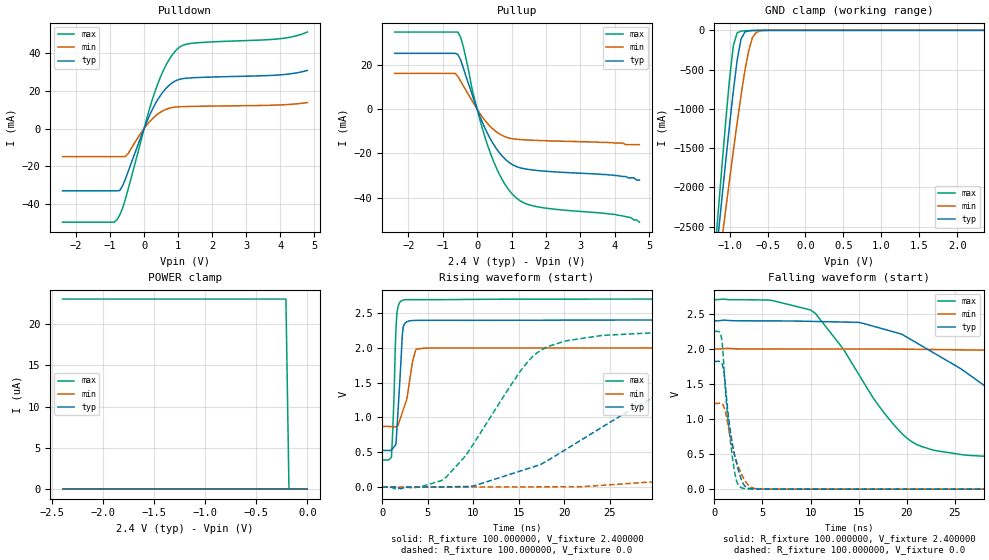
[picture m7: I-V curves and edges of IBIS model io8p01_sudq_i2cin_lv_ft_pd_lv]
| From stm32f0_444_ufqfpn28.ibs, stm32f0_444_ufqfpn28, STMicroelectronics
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|   Model io8p01_sudq_i2cin_lv_ft_pd_lv
[Model]  io8p01_sudq_i2cin_lv_ft_pd_lv
Model_type I/O
Polarity   Non-Inverting
Enable   Active-Low
Vinl =   0.720000V
Vinh =   1.680000V
Vmeas =  1.200000V
Cref =   50.000000pF
Rref =   100.000000M
Vref =   0.0V
C_comp   2.067900pF   1.988600pF   2.164800pF
[Temperature Range]   25.000000   0.125000k   -40.000000
[Pullup Reference]   2.400000V   2.000000V   2.700000V
[Pulldown Reference]   0.0V   0.0V   0.0V
[POWER Clamp Reference]   2.400000V   2.000000V   2.700000V
[GND Clamp Reference]   0.0V   0.0V   0.0V
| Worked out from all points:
|   slope of the pulldown table from 0 to 0.36 V, typ, clamps not added: 25.5 ohm
|   slope of the pullup table from 0 to 0.36 V, typ, clamps not added: 28.4 ohm
|   GND clamp passes 1 mA (typ) near -0.64 V on its own axis
|   rising waveform, R_fixture 100.000000, V_fixture 2.400000: 20-80 % time 500ps typ, 1.02ns min, 335ps max; typ from 0.525 V to 2.4 V
|   rising waveform, R_fixture 100.000000, V_fixture 0.0: 20-80 % time 14.6ns typ, 43.1ns min, 6.86ns max; typ from 0 V to 1.82 V
|   falling waveform, R_fixture 100.000000, V_fixture 2.400000: 20-80 % time 12.9ns typ, 31.1ns min, 7.07ns max; typ from 2.4 V to 0.525 V
|   falling waveform, R_fixture 100.000000, V_fixture 0.0: 20-80 % time 1.16ns typ, 1.39ns min, 919ps max; typ from 1.82 V to 0 V
[Pulldown]
|Voltage   I(typ)   I(min)   I(max)
-2.4V     -33.16mA   -14.98mA   -49.86mA
-880mV    -33.16mA   -14.98mA   -49.86mA
-800mV    -33.16mA   -14.98mA   -48.55mA
-640mV    -30.75mA   -14.98mA   -42.77mA
-480mV    -23.43mA   -13.57mA   -32.92mA
80mV      3.651mA    1.905mA    5.506mA
400mV     15.37mA    7.665mA    23.73mA
720mV     22.75mA    10.69mA    36.23mA
1.04V     26.18mA    11.57mA    43.27mA
1.52V     27.09mA    11.81mA    45.55mA
4V        28.55mA    12.55mA    47.81mA
4.8V      30.9mA     13.81mA    51.31mA
[Pullup]
|Voltage   I(typ)   I(min)   I(max)
-2.4V     25.18mA    16.13mA    34.78mA
-640mV    25.18mA    16.13mA    34.78mA
-560mV    24.71mA    14.76mA    34.78mA
-400mV    18.52mA    10.49mA    28.1mA
-160mV    7.343mA    4.152mA    10.02mA
80mV      -3.229mA   -1.94mA    -4.736mA
400mV     -13.82mA   -8.08mA    -20.45mA
800mV     -22.31mA   -12.38mA   -33.66mA
1.2V      -26.24mA   -13.65mA   -40.82mA
1.76V     -27.69mA   -14.12mA   -44.06mA
4V        -29.9mA    -15.3mA    -47.5mA
4.72V     -32mA      -16mA      -51mA
[GND_clamp]
|Voltage   I(typ)   I(min)   I(max)
-2.4V     -9.567A    -9.921A    -9.731A
-1.2V     -3.09A     -3.428A    -2.911A
-1.15V    -2.606A    -3.04A     -2.31A
-1.1V     -2.127A    -2.655A    -1.719A
-1.05V    -1.657A    -2.274A    -1.146A
-950mV    -765.3mA   -1.53A     -190.2mA
-900mV    -376.6mA   -1.172A    -30.82mA
-850mV    -112.3mA   -832.5mA   -10.25mA
-750mV    -6.584mA   -264.6mA   -4.043mA
-700mV    -2.596mA   -94.27mA   -2.346mA
-600mV    -430uA     -8.168mA   -383.4uA
2.35V     59.64uA    46.24uA    66.77uA
[POWER_clamp]
|Voltage   I(typ)   I(min)   I(max)
-2.4V     0A         0A         23.03uA
-210mV    0A         0A         23.03uA
-180mV    0A         0A         0A
0V        0A         0A         0A
[Ramp]
| variable   typ   min   max
dV/dt_r  1.09212/14.56809n   0.73266/43.05273n   1.34886/6.82630n
dV/dt_f  1.12434/12.85256n   0.67775/31.09011n   1.38699/7.06475n
R_load = 100.000000
[Rising Waveform]
R_fixture= 100.000000
V_fixture= 2.400000
V_fixture_min= 2.000000
V_fixture_max= 2.700000
|time   V(typ)   V(min)   V(max)
0s        524.8mV    868.7mV    387.2mV
1.001ns   532.9mV    867mV      427.3mV
1.301ns   579.1mV    865.4mV    1.37V
1.401ns   594.6mV    865.1mV    1.926V
1.502ns   617.3mV    864.8mV    2.291V
1.702ns   1.048V     875.3mV    2.575V
2.202ns   2.193V     1.071V     2.68V
2.603ns   2.365V     1.228V     2.689V
3.704ns   2.393V     1.98V      2.691V
49.85ns   2.399V     1.999V     2.699V
[Rising Waveform]
R_fixture= 100.000000
V_fixture= 0.0
V_fixture_min= 0.0
V_fixture_max= 0.0
|time   V(typ)   V(min)   V(max)
0s        1.433nV    15.35nV    1.088nV
6.507ns   646.2uV    89.27uV    90.97mV
9.51ns    7.691mV    -441.4uV   514.6mV
16.52ns   284.6mV    1.37mV     1.871V
24.52ns   887.2mV    26.48mV    2.179V
36.54ns   1.614V     133.7mV    2.237V
56.06ns   1.793V     469.1mV    2.248V
89.09ns   1.819V     1.005V     2.248V
109.1ns   1.82V      1.141V     2.248V
249.2ns   1.82V      1.221V     2.248V
[Falling Waveform]
R_fixture= 100.000000
V_fixture= 2.400000
V_fixture_min= 2.000000
V_fixture_max= 2.700000
|time   V(typ)   V(min)   V(max)
0s        2.399V     1.999V     2.699V
10.01ns   2.391V     1.997V     2.553V
19.52ns   2.206V     1.995V     791.1mV
21.52ns   2.046V     1.992V     609.9mV
26.53ns   1.629V     1.984V     481.2mV
36.54ns   807.6mV    1.943V     420.5mV
53.55ns   588mV      1.622V     394.4mV
78.08ns   540.8mV    1.104V     387.6mV
101.6ns   527.3mV    957mV      387.2mV
249.2ns   524.8mV    868.7mV    387.2mV
[Falling Waveform]
R_fixture= 100.000000
V_fixture= 0.0
V_fixture_min= 0.0
V_fixture_max= 0.0
|time   V(typ)   V(min)   V(max)
0s        1.82V      1.221V     2.248V
700.7ps   1.801V     1.221V     2.179V
1.001ns   1.654V     1.164V     1.708V
1.401ns   1.096V     924.5mV    1.005V
1.902ns   621.1mV    594.7mV    425.5mV
2.302ns   372.5mV    389.7mV    120.1mV
2.903ns   102.4mV    190.5mV    15.79mV
3.704ns   10.24mV    37.9mV     2.222mV
5.005ns   1.166mV    2.421mV    746.2uV
49.85ns   1.433nV    15.35nV    1.088nV
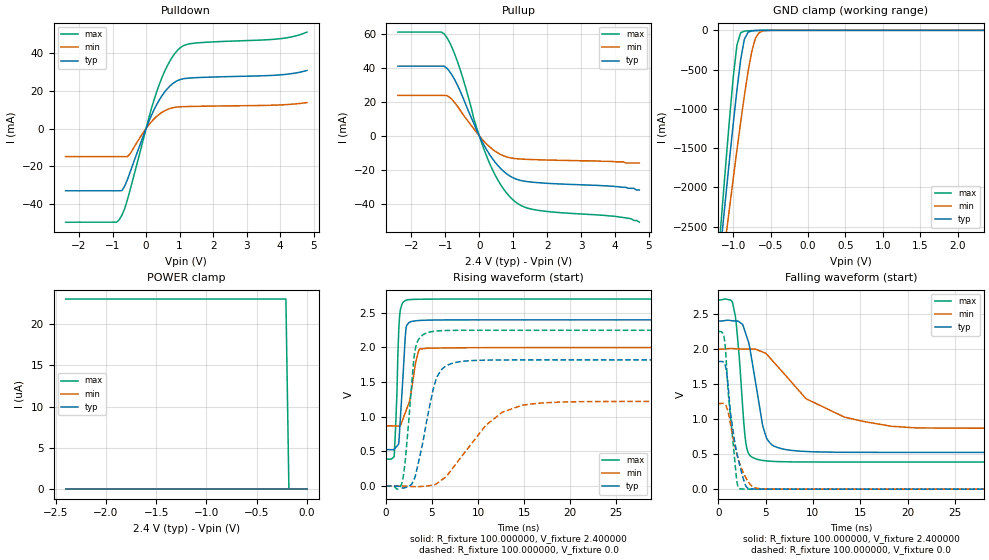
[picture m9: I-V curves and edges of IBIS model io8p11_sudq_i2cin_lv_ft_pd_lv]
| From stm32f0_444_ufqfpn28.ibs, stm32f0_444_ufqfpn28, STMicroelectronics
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|   Model io8p11_sudq_i2cin_lv_ft_pd_lv
[Model]  io8p11_sudq_i2cin_lv_ft_pd_lv
Model_type I/O
Polarity   Non-Inverting
Enable   Active-Low
Vinl =   0.720000V
Vinh =   1.680000V
Vmeas =  1.200000V
Cref =   50.000000pF
Rref =   100.000000M
Vref =   0.0V
C_comp   2.067900pF   1.988600pF   2.164800pF
[Temperature Range]   25.000000   0.125000k   -40.000000
[Pullup Reference]   2.400000V   2.000000V   2.700000V
[Pulldown Reference]   0.0V   0.0V   0.0V
[POWER Clamp Reference]   2.400000V   2.000000V   2.700000V
[GND Clamp Reference]   0.0V   0.0V   0.0V
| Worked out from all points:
|   slope of the pulldown table from 0 to 0.36 V, typ, clamps not added: 25.5 ohm
|   slope of the pullup table from 0 to 0.36 V, typ, clamps not added: 28.4 ohm
|   GND clamp passes 1 mA (typ) near -0.64 V on its own axis
|   rising waveform, R_fixture 100.000000, V_fixture 2.400000: 20-80 % time 510ps typ, 1.01ns min, 339ps max; typ from 0.525 V to 2.4 V
|   rising waveform, R_fixture 100.000000, V_fixture 0.0: 20-80 % time 1.69ns typ, 4.61ns min, 850ps max; typ from 0 V to 1.82 V
|   falling waveform, R_fixture 100.000000, V_fixture 2.400000: 20-80 % time 1.38ns typ, 6.16ns min, 775ps max; typ from 2.4 V to 0.525 V
|   falling waveform, R_fixture 100.000000, V_fixture 0.0: 20-80 % time 1.18ns typ, 1.39ns min, 859ps max; typ from 1.82 V to 0 V
[Pulldown]
|Voltage   I(typ)   I(min)   I(max)
-2.4V     -33.16mA   -14.98mA   -49.86mA
-880mV    -33.16mA   -14.98mA   -49.86mA
-800mV    -33.16mA   -14.98mA   -48.55mA
-640mV    -30.75mA   -14.98mA   -42.77mA
-480mV    -23.43mA   -13.57mA   -32.92mA
80mV      3.651mA    1.905mA    5.506mA
400mV     15.37mA    7.665mA    23.73mA
720mV     22.75mA    10.69mA    36.23mA
1.04V     26.18mA    11.57mA    43.27mA
1.52V     27.09mA    11.81mA    45.55mA
4V        28.55mA    12.55mA    47.81mA
4.8V      30.9mA     13.81mA    51.31mA
[Pullup]
|Voltage   I(typ)   I(min)   I(max)
-2.4V     41.21mA    23.93mA    61.35mA
-1.12V    41.21mA    23.93mA    61.35mA
-960mV    40.07mA    23.79mA    58.27mA
-800mV    35.79mA    21.42mA    51.96mA
-560mV    26.32mA    15.02mA    38.93mA
-160mV    7.343mA    4.152mA    10.02mA
240mV     -8.976mA   -5.327mA   -13.21mA
640mV     -19.5mA    -11.09mA   -29.16mA
1.04V     -25.15mA   -13.38mA   -38.61mA
1.68V     -27.56mA   -14.07mA   -43.81mA
4V        -29.9mA    -15.3mA    -47.5mA
4.72V     -32mA      -16mA      -51mA
[GND_clamp]
|Voltage   I(typ)   I(min)   I(max)
-2.4V     -9.567A    -9.921A    -9.731A
-1.2V     -3.09A     -3.428A    -2.911A
-1.15V    -2.606A    -3.04A     -2.31A
-1.1V     -2.127A    -2.655A    -1.719A
-1.05V    -1.657A    -2.274A    -1.146A
-950mV    -765.3mA   -1.53A     -190.2mA
-900mV    -376.6mA   -1.172A    -30.82mA
-850mV    -112.3mA   -832.5mA   -10.25mA
-750mV    -6.584mA   -264.6mA   -4.043mA
-700mV    -2.596mA   -94.27mA   -2.346mA
-600mV    -430uA     -8.168mA   -383.4uA
2.35V     59.64uA    46.24uA    66.77uA
[POWER_clamp]
|Voltage   I(typ)   I(min)   I(max)
-2.4V     0A         0A         23.03uA
-210mV    0A         0A         23.03uA
-180mV    0A         0A         0A
0V        0A         0A         0A
[Ramp]
| variable   typ   min   max
dV/dt_r  1.09212/1.68415n   0.73266/4.61016n   1.34886/0.84941n
dV/dt_f  1.12444/1.38089n   0.67800/6.15833n   1.38697/0.77173n
R_load = 100.000000
[Rising Waveform]
R_fixture= 100.000000
V_fixture= 2.400000
V_fixture_min= 2.000000
V_fixture_max= 2.700000
|time   V(typ)   V(min)   V(max)
0s        524.8mV    868.7mV    387.2mV
900.9ps   532.3mV    867.2mV    423.3mV
1.201ns   574.8mV    865.9mV    1.333V
1.401ns   610.4mV    865.5mV    2.262V
1.602ns   1.033V     875.3mV    2.56V
2.202ns   2.295V     1.092V     2.683V
2.603ns   2.367V     1.236V     2.691V
3.203ns   2.384V     1.759V     2.695V
3.704ns   2.39V      1.979V     2.696V
49.85ns   2.399V     1.999V     2.699V
[Rising Waveform]
R_fixture= 100.000000
V_fixture= 0.0
V_fixture_min= 0.0
V_fixture_max= 0.0
|time   V(typ)   V(min)   V(max)
0s        -33.69uV   -15.69uV   -30.68uV
1.802ns   -28.98mV   -1.309mV   64.92mV
2.102ns   -23.72mV   -2.964mV   356.8mV
3.103ns   108.8mV    -9.663mV   1.904V
4.505ns   986.4mV    148.2uV    2.213V
5.405ns   1.521V     24.05mV    2.236V
6.406ns   1.722V     120.1mV    2.245V
10.91ns   1.818V     883mV      2.248V
14.81ns   1.82V      1.166V     2.248V
49.85ns   1.82V      1.221V     2.248V
[Falling Waveform]
R_fixture= 100.000000
V_fixture= 2.400000
V_fixture_min= 2.000000
V_fixture_max= 2.700000
|time   V(typ)   V(min)   V(max)
0s        2.399V     1.999V     2.699V
1.502ns   2.401V     2.006V     2.67V
1.902ns   2.399V     2.002V     2.369V
2.903ns   2.22V      1.998V     672.6mV
4.004ns   1.475V     1.993V     430.7mV
5.105ns   725.9mV    1.927V     403.1mV
7.307ns   561.2mV    1.593V     390.3mV
13.21ns   526.2mV    1.035V     387.1mV
18.32ns   524.6mV    896.8mV    387.3mV
49.85ns   524.8mV    868.7mV    387.2mV
[Falling Waveform]
R_fixture= 100.000000
V_fixture= 0.0
V_fixture_min= 0.0
V_fixture_max= 0.0
|time   V(typ)   V(min)   V(max)
0s        1.82V      1.221V     2.248V
500.5ps   1.818V     1.226V     2.221V
700.7ps   1.782V     1.213V     2.101V
1.001ns   1.542V     1.126V     1.487V
1.301ns   1.087V     925.7mV    1.022V
1.902ns   558.9mV    540.5mV    190.6mV
2.202ns   380.4mV    392.4mV    9.067mV
3.003ns   29.33mV    139.9mV    1.272mV
4.605ns   1.016mV    5.593mV    355uV
49.85ns   -33.69uV   -15.69uV   -30.68uV
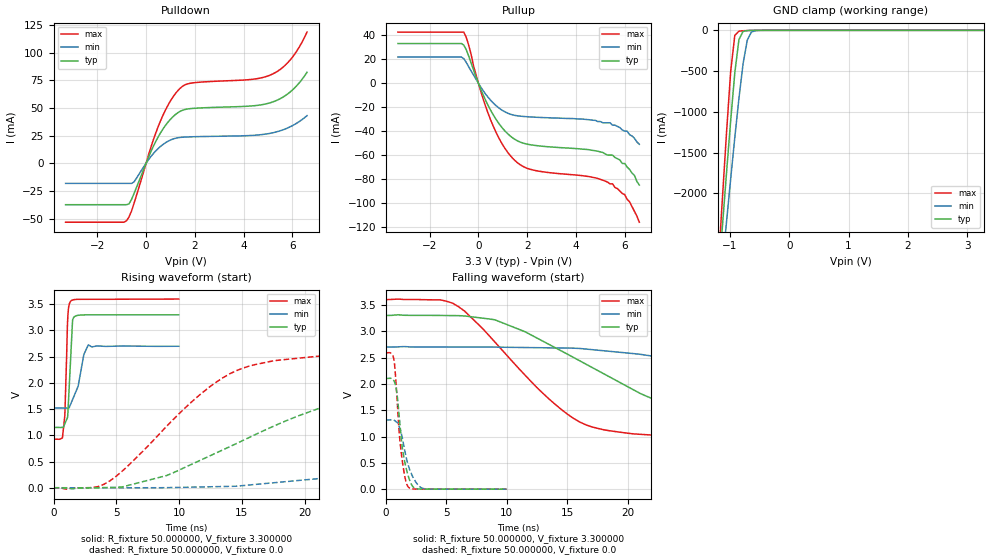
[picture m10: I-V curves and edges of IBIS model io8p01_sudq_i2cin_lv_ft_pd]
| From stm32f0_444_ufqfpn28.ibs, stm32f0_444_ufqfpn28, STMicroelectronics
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|   Model io8p01_sudq_i2cin_lv_ft_pd
[Model]  io8p01_sudq_i2cin_lv_ft_pd
Model_type I/O
Polarity   Non-Inverting
Enable   Active-Low
Vinl =   0.990000V
Vinh =   2.310000V
Vmeas =  1.650000V
Cref =   50.000000pF
Rref =   100.000000M
Vref =   0.0V
C_comp   2.070000pF   1.996000pF   2.160200pF
[Temperature Range]   25.000000   0.125000k   -40.000000
[Pullup Reference]   3.300000V   2.700000V   3.600000V
[Pulldown Reference]   0.0V   0.0V   0.0V
[POWER Clamp Reference]   3.300000V   2.700000V   3.600000V
[GND Clamp Reference]   0.0V   0.0V   0.0V
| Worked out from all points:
|   slope of the pulldown table from 0 to 0.495 V, typ, clamps not added: 20.9 ohm
|   slope of the pullup table from 0 to 0.495 V, typ, clamps not added: 22.2 ohm
|   GND clamp passes 1 mA (typ) near -0.64 V on its own axis
|   rising waveform, R_fixture 50.000000, V_fixture 3.300000: 20-80 % time 272ps typ, 710ps min, 191ps max; typ from 1.15 V to 3.3 V
|   rising waveform, R_fixture 50.000000, V_fixture 0.0: 20-80 % time 12.7ns typ, 30.7ns min, 6.96ns max; typ from 0 V to 2.1 V
|   falling waveform, R_fixture 50.000000, V_fixture 3.300000: 20-80 % time 11ns typ, 22.8ns min, 6.87ns max; typ from 3.3 V to 1.15 V
|   falling waveform, R_fixture 50.000000, V_fixture 0.0: 20-80 % time 669ps typ, 882ps min, 549ps max; typ from 2.1 V to 0 V
[Pulldown]
|Voltage   I(typ)   I(min)   I(max)
-3.3V     -37.45mA   -18.2mA    -53.24mA
-800mV    -37.45mA   -18.2mA    -51.9mA
-700mV    -36.7mA    -18.2mA    -48.48mA
-500mV    -27.71mA   -17.01mA   -36.66mA
200mV     10.57mA    6.084mA    14.57mA
500mV     23.91mA    13.38mA    33.24mA
900mV     37.17mA    19.88mA    52.48mA
1.3V      45.55mA    23.01mA    65.5mA
1.8V      49.29mA    23.83mA    72.18mA
5.1V      54.68mA    27.07mA    79.72mA
5.9V      64.2mA     32.82mA    93.01mA
6.6V      82.13mA    42.97mA    118.5mA
[Pullup]
|Voltage   I(typ)   I(min)   I(max)
-3.3V     33.15mA    21.88mA    42.69mA
-600mV    31.87mA    20.58mA    42.69mA
-400mV    22.8mA     13.77mA    31.9mA
100mV     -5.13mA    -3.299mA   -6.952mA
500mV     -22.5mA    -14.16mA   -30.52mA
900mV     -35.28mA   -21.55mA   -48mA
1.4V      -45.54mA   -26.4mA    -62.54mA
2.2V      -51.57mA   -28.22mA   -72.25mA
4.6V      -55.8mA    -30.6mA    -78.18mA
5.5V      -60mA      -35mA      -84mA
6V        -67mA      -40mA      -93mA
6.6V      -85mA      -51mA      -116mA
[GND_clamp]
|Voltage   I(typ)   I(min)   I(max)
-3.3V     -9.366A    -9.678A    -9.859A
-1.2V     -3.091A    -3.431A    -2.911A
-1.13V    -2.415A    -2.888A    -2.072A
-1.06V    -1.751A    -2.352A    -1.259A
-990mV    -1.112A    -1.826A    -509.3mA
-920mV    -522.9mA   -1.315A    -61.63mA
-850mV    -112.6mA   -833.9mA   -10.23mA
-780mV    -13.61mA   -408.1mA   -5.273mA
-710mV    -3.095mA   -122.1mA   -2.651mA
-640mV    -959.2uA   -21.37mA   -921.5uA
-570mV    -212.9uA   -4.153mA   -172uA
3.28V     83.63uA    63.62uA    93.37uA
[POWER_clamp]
|Voltage   I(typ)   I(min)   I(max)
-3.28V    0A         0A         0A
0V        0A         0A         0A
[Ramp]
| variable   typ   min   max
dV/dt_r  1.26144/12.63190n   0.78864/30.65469n   1.55376/6.94839n
dV/dt_f  1.28928/10.98369n   0.70662/22.76969n   1.60432/6.85767n
R_load = 50.000000
[Rising Waveform]
R_fixture= 50.000000
V_fixture= 3.300000
V_fixture_min= 2.700000
V_fixture_max= 3.600000
|time   V(typ)   V(min)   V(max)
0s        1.15V      1.52V      925.1mV
720.7ps   1.152V     1.52V      977.6mV
900.9ps   1.22V      1.519V     1.38V
1.121ns   1.345V     1.52V      3.179V
1.201ns   1.701V     1.52V      3.438V
1.361ns   2.459V     1.593V     3.558V
1.522ns   3.204V     1.685V     3.581V
2.422ns   3.297V     2.547V     3.594V
2.783ns   3.297V     2.724V     3.595V
9.97ns    3.299V     2.699V     3.599V
[Rising Waveform]
R_fixture= 50.000000
V_fixture= 0.0
V_fixture_min= 0.0
V_fixture_max= 0.0
|time   V(typ)   V(min)   V(max)
0s        1.621nV    10.89nV    2.151nV
4.505ns   5.511mV    6.201uV    133.7mV
9.009ns   233.4mV    1.74mV     1.174V
14.01ns   781.6mV    25.89mV    2.171V
21.52ns   1.547V     183.3mV    2.516V
27.03ns   1.865V     313.2mV    2.56V
33.53ns   2.007V     513.8mV    2.579V
51.55ns   2.093V     981.4mV    2.591V
68.57ns   2.1V       1.198V     2.59V
249.2ns   2.102V     1.315V     2.59V
[Falling Waveform]
R_fixture= 50.000000
V_fixture= 3.300000
V_fixture_min= 2.700000
V_fixture_max= 3.600000
|time   V(typ)   V(min)   V(max)
0s        3.299V     2.699V     3.599V
4.505ns   3.298V     2.699V     3.594V
6.006ns   3.295V     2.699V     3.465V
9.009ns   3.216V     2.697V     2.793V
13.01ns   2.805V     2.685V     1.813V
16.02ns   2.438V     2.672V     1.276V
24.52ns   1.501V     2.44V      989.6mV
41.54ns   1.206V     1.846V     934.9mV
65.57ns   1.159V     1.6V       925.3mV
249.2ns   1.15V      1.52V      925.1mV
[Falling Waveform]
R_fixture= 50.000000
V_fixture= 0.0
V_fixture_min= 0.0
V_fixture_max= 0.0
|time   V(typ)   V(min)   V(max)
0s        2.102V     1.315V     2.59V
660.7ps   2.061V     1.314V     2.465V
900.9ps   1.842V     1.272V     1.806V
1.081ns   1.439V     1.204V     1.139V
1.221ns   1.085V     1.113V     789.1mV
1.562ns   516.8mV    732.2mV    247.1mV
1.862ns   241.1mV    448.9mV    37.76mV
2.322ns   28.13mV    193.2mV    2.91mV
3.083ns   1.42mV     12.15mV    413.8uV
9.97ns    1.621nV    10.89nV    2.151nV
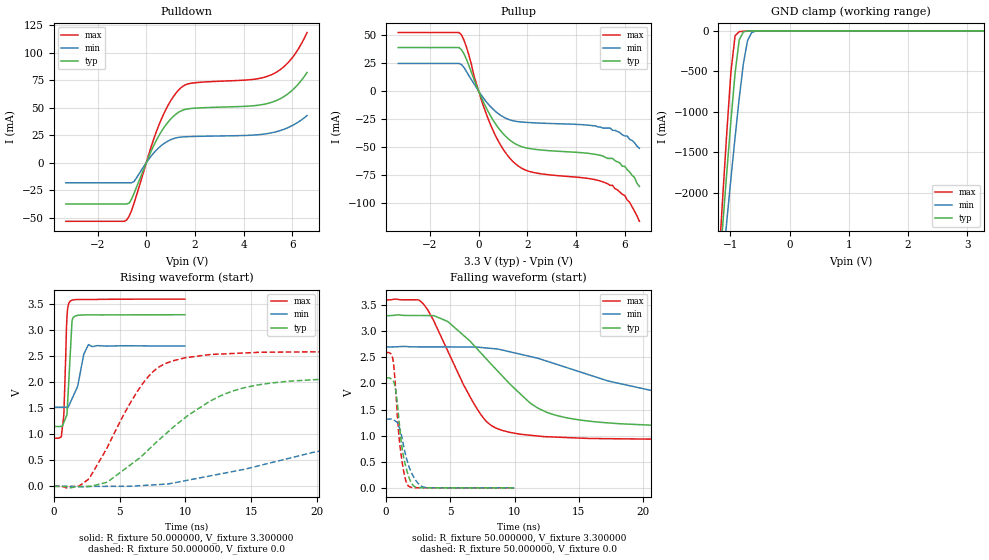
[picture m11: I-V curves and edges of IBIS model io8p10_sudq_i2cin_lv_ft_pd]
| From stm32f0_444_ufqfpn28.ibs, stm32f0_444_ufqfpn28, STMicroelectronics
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|   Model io8p10_sudq_i2cin_lv_ft_pd
[Model]  io8p10_sudq_i2cin_lv_ft_pd
Model_type I/O
Polarity   Non-Inverting
Enable   Active-Low
Vinl =   0.990000V
Vinh =   2.310000V
Vmeas =  1.650000V
Cref =   50.000000pF
Rref =   100.000000M
Vref =   0.0V
C_comp   2.070000pF   1.996000pF   2.160200pF
[Temperature Range]   25.000000   0.125000k   -40.000000
[Pullup Reference]   3.300000V   2.700000V   3.600000V
[Pulldown Reference]   0.0V   0.0V   0.0V
[POWER Clamp Reference]   3.300000V   2.700000V   3.600000V
[GND Clamp Reference]   0.0V   0.0V   0.0V
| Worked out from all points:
|   slope of the pulldown table from 0 to 0.495 V, typ, clamps not added: 20.9 ohm
|   slope of the pullup table from 0 to 0.495 V, typ, clamps not added: 22.2 ohm
|   GND clamp passes 1 mA (typ) near -0.64 V on its own axis
|   rising waveform, R_fixture 50.000000, V_fixture 3.300000: 20-80 % time 274ps typ, 706ps min, 192ps max; typ from 1.15 V to 3.3 V
|   rising waveform, R_fixture 50.000000, V_fixture 0.0: 20-80 % time 6.36ns typ, 15ns min, 3.52ns max; typ from 0 V to 2.1 V
|   falling waveform, R_fixture 50.000000, V_fixture 3.300000: 20-80 % time 5.22ns typ, 10.6ns min, 3.26ns max; typ from 3.3 V to 1.15 V
|   falling waveform, R_fixture 50.000000, V_fixture 0.0: 20-80 % time 669ps typ, 882ps min, 547ps max; typ from 2.1 V to 0 V
[Pulldown]
|Voltage   I(typ)   I(min)   I(max)
-3.3V     -37.45mA   -18.2mA    -53.24mA
-800mV    -37.45mA   -18.2mA    -51.9mA
-700mV    -36.7mA    -18.2mA    -48.48mA
-500mV    -27.71mA   -17.01mA   -36.66mA
200mV     10.57mA    6.084mA    14.57mA
500mV     23.91mA    13.38mA    33.24mA
900mV     37.17mA    19.88mA    52.48mA
1.3V      45.55mA    23.01mA    65.5mA
1.8V      49.29mA    23.83mA    72.18mA
5.1V      54.68mA    27.07mA    79.72mA
5.9V      64.2mA     32.82mA    93.01mA
6.6V      82.13mA    42.97mA    118.5mA
[Pullup]
|Voltage   I(typ)   I(min)   I(max)
-3.3V     38.72mA    24.59mA    52.09mA
-800mV    38.72mA    24.59mA    52.09mA
-500mV    28.38mA    17.49mA    39.2mA
0V        0A         0A         0A
500mV     -22.5mA    -14.16mA   -30.52mA
900mV     -35.28mA   -21.55mA   -48mA
1.4V      -45.54mA   -26.4mA    -62.54mA
2.2V      -51.57mA   -28.22mA   -72.25mA
4.6V      -55.8mA    -30.6mA    -78.18mA
5.5V      -60mA      -35mA      -84mA
6V        -67mA      -40mA      -93mA
6.6V      -85mA      -51mA      -116mA
[GND_clamp]
|Voltage   I(typ)   I(min)   I(max)
-3.3V     -9.366A    -9.678A    -9.859A
-1.2V     -3.091A    -3.431A    -2.911A
-1.13V    -2.415A    -2.888A    -2.072A
-1.06V    -1.751A    -2.352A    -1.259A
-990mV    -1.112A    -1.826A    -509.3mA
-920mV    -522.9mA   -1.315A    -61.63mA
-850mV    -112.6mA   -833.9mA   -10.23mA
-780mV    -13.61mA   -408.1mA   -5.273mA
-710mV    -3.095mA   -122.1mA   -2.651mA
-640mV    -959.2uA   -21.37mA   -921.5uA
-570mV    -212.9uA   -4.153mA   -172uA
3.28V     83.63uA    63.62uA    93.37uA
[POWER_clamp]
|Voltage   I(typ)   I(min)   I(max)
-3.28V    0A         0A         0A
0V        0A         0A         0A
[Ramp]
| variable   typ   min   max
dV/dt_r  1.26132/6.35588n   0.77886/15.03360n   1.55388/3.51935n
dV/dt_f  1.28922/5.21575n   0.69978/10.66026n   1.60432/3.25744n
R_load = 50.000000
[Rising Waveform]
R_fixture= 50.000000
V_fixture= 3.300000
V_fixture_min= 2.700000
V_fixture_max= 3.600000
|time   V(typ)   V(min)   V(max)
0s        1.15V      1.521V     925.1mV
580.6ps   1.152V     1.52V      976.3mV
760.8ps   1.227V     1.519V     1.369V
1.001ns   1.378V     1.52V      3.261V
1.221ns   2.41V      1.591V     3.554V
1.401ns   3.2V       1.693V     3.58V
1.822ns   3.287V     1.931V     3.591V
2.282ns   3.295V     2.542V     3.591V
2.643ns   3.295V     2.725V     3.591V
9.97ns    3.299V     2.699V     3.599V
[Rising Waveform]
R_fixture= 50.000000
V_fixture= 0.0
V_fixture_min= 0.0
V_fixture_max= 0.0
|time   V(typ)   V(min)   V(max)
0s        -32.59uV   -22.87uV   -20.67uV
2.603ns   -258.7uV   -5.435mV   128.9mV
4.104ns   86.96mV    -423.7uV   768.1mV
6.907ns   633mV      17.85mV    2.022V
8.108ns   916.5mV    36.11mV    2.31V
9.91ns    1.303V     104.1mV    2.467V
13.71ns   1.84V      289mV      2.555V
18.02ns   2.023V     546.9mV    2.582V
30.23ns   2.097V     1.112V     2.59V
49.85ns   2.103V     1.315V     2.59V
[Falling Waveform]
R_fixture= 50.000000
V_fixture= 3.300000
V_fixture_min= 2.700000
V_fixture_max= 3.600000
|time   V(typ)   V(min)   V(max)
0s        3.299V     2.699V     3.599V
2.903ns   3.3V       2.699V     3.52V
4.805ns   3.184V     2.699V     2.618V
7.207ns   2.629V     2.692V     1.465V
8.208ns   2.361V     2.67V      1.192V
9.61ns    1.995V     2.607V     1.064V
12.51ns   1.446V     2.427V     978.9mV
16.62ns   1.257V     2.099V     943.4mV
27.03ns   1.166V     1.651V     926.3mV
49.85ns   1.15V      1.521V     925.1mV
[Falling Waveform]
R_fixture= 50.000000
V_fixture= 0.0
V_fixture_min= 0.0
V_fixture_max= 0.0
|time   V(typ)   V(min)   V(max)
0s        2.103V     1.315V     2.59V
520.5ps   2.061V     1.313V     2.468V
760.8ps   1.845V     1.272V     1.815V
940.9ps   1.444V     1.206V     1.144V
1.081ns   1.091V     1.116V     793.8mV
1.421ns   518.7mV    733.7mV    248.1mV
1.722ns   242.5mV    449.7mV    38.9mV
2.102ns   45.62mV    228mV      4.887mV
2.903ns   2.061mV    14.82mV    1.6mV
9.97ns    -32.59uV   -22.87uV   -20.67uV
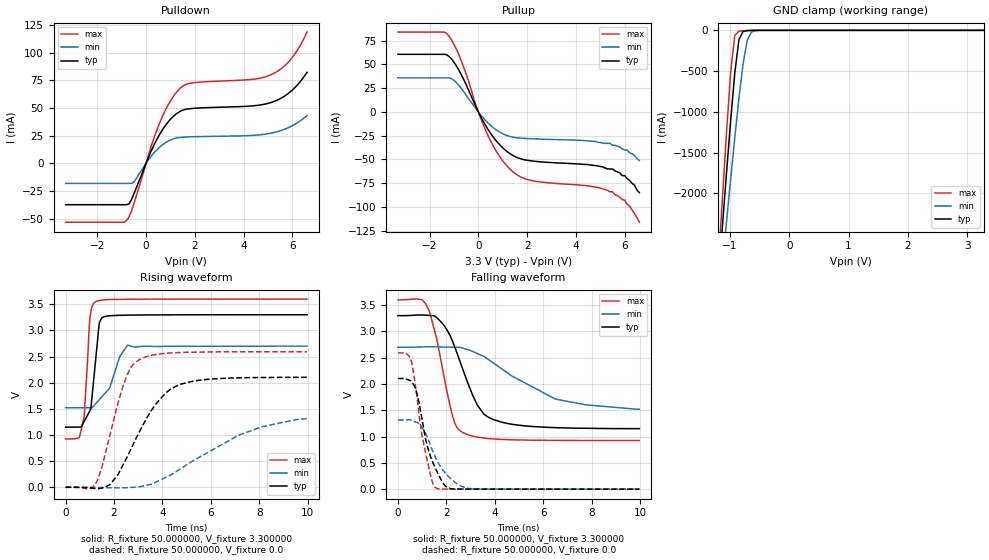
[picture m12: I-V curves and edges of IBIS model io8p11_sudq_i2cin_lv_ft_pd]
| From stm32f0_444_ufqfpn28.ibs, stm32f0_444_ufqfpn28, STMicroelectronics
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|   Model io8p11_sudq_i2cin_lv_ft_pd
[Model]  io8p11_sudq_i2cin_lv_ft_pd
Model_type I/O
Polarity   Non-Inverting
Enable   Active-Low
Vinl =   0.990000V
Vinh =   2.310000V
Vmeas =  1.650000V
Cref =   30.000000pF
Rref =   100.000000M
Vref =   0.0V
C_comp   2.070000pF   1.996000pF   2.160200pF
[Temperature Range]   25.000000   0.125000k   -40.000000
[Pullup Reference]   3.300000V   2.700000V   3.600000V
[Pulldown Reference]   0.0V   0.0V   0.0V
[POWER Clamp Reference]   3.300000V   2.700000V   3.600000V
[GND Clamp Reference]   0.0V   0.0V   0.0V
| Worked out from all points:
|   slope of the pulldown table from 0 to 0.495 V, typ, clamps not added: 20.9 ohm
|   slope of the pullup table from 0 to 0.495 V, typ, clamps not added: 22.2 ohm
|   GND clamp passes 1 mA (typ) near -0.64 V on its own axis
|   rising waveform, R_fixture 50.000000, V_fixture 3.300000: 20-80 % time 272ps typ, 664ps min, 195ps max; typ from 1.15 V to 3.3 V
|   rising waveform, R_fixture 50.000000, V_fixture 0.0: 20-80 % time 1.53ns typ, 3.04ns min, 906ps max; typ from 0 V to 2.1 V
|   falling waveform, R_fixture 50.000000, V_fixture 3.300000: 20-80 % time 1.1ns typ, 2.59ns min, 731ps max; typ from 3.3 V to 1.15 V
|   falling waveform, R_fixture 50.000000, V_fixture 0.0: 20-80 % time 671ps typ, 889ps min, 535ps max; typ from 2.1 V to 0 V
[Pulldown]
|Voltage   I(typ)   I(min)   I(max)
-3.3V     -37.45mA   -18.2mA    -53.24mA
-800mV    -37.45mA   -18.2mA    -51.9mA
-700mV    -36.7mA    -18.2mA    -48.48mA
-500mV    -27.71mA   -17.01mA   -36.66mA
200mV     10.57mA    6.084mA    14.57mA
500mV     23.91mA    13.38mA    33.24mA
900mV     37.17mA    19.88mA    52.48mA
1.3V      45.55mA    23.01mA    65.5mA
1.8V      49.29mA    23.83mA    72.18mA
5.1V      54.68mA    27.07mA    79.72mA
5.9V      64.2mA     32.82mA    93.01mA
6.6V      82.13mA    42.97mA    118.5mA
[Pullup]
|Voltage   I(typ)   I(min)   I(max)
-3.3V     60.68mA    35.91mA    84.09mA
-1.4V     60.68mA    35.91mA    84.09mA
-1.2V     58.38mA    35.91mA    79.68mA
-700mV    39.19mA    24.86mA    53.71mA
0V        0A         0A         0A
400mV     -18.61mA   -11.78mA   -25.23mA
900mV     -35.28mA   -21.55mA   -48mA
1.5V      -46.91mA   -26.86mA   -64.57mA
2.2V      -51.57mA   -28.22mA   -72.25mA
5.5V      -60mA      -35mA      -84mA
6V        -67mA      -40mA      -93mA
6.6V      -85mA      -51mA      -116mA
[GND_clamp]
|Voltage   I(typ)   I(min)   I(max)
-3.3V     -9.366A    -9.678A    -9.859A
-1.2V     -3.091A    -3.431A    -2.911A
-1.13V    -2.415A    -2.888A    -2.072A
-1.06V    -1.751A    -2.352A    -1.259A
-990mV    -1.112A    -1.826A    -509.3mA
-920mV    -522.9mA   -1.315A    -61.63mA
-850mV    -112.6mA   -833.9mA   -10.23mA
-780mV    -13.61mA   -408.1mA   -5.273mA
-710mV    -3.095mA   -122.1mA   -2.651mA
-640mV    -959.2uA   -21.37mA   -921.5uA
-570mV    -212.9uA   -4.153mA   -172uA
3.28V     83.63uA    63.62uA    93.37uA
[POWER_clamp]
|Voltage   I(typ)   I(min)   I(max)
-3.28V    0A         0A         0A
0V        0A         0A         0A
[Ramp]
| variable   typ   min   max
dV/dt_r  1.26108/1.53380n   0.73980/3.03420n   1.55376/0.90454n
dV/dt_f  1.28808/1.10363n   0.68718/2.57370n   1.60432/0.73008n
R_load = 50.000000
[Rising Waveform]
R_fixture= 50.000000
V_fixture= 3.300000
V_fixture_min= 2.700000
V_fixture_max= 3.600000
|time   V(typ)   V(min)   V(max)
0s        1.15V      1.521V     925.1mV
560.6ps   1.152V     1.52V      945.5mV
760.8ps   1.254V     1.519V     1.333V
1.001ns   1.461V     1.52V      3.214V
1.221ns   2.343V     1.586V     3.542V
1.381ns   3.103V     1.67V      3.57V
1.502ns   3.244V     1.732V     3.58V
1.822ns   3.279V     1.901V     3.589V
2.563ns   3.291V     2.718V     3.595V
9.97ns    3.299V     2.699V     3.599V
[Rising Waveform]
R_fixture= 50.000000
V_fixture= 0.0
V_fixture_min= 0.0
V_fixture_max= 0.0
|time   V(typ)   V(min)   V(max)
0s        -16.77uV   -27.94uV   -14.14uV
1.201ns   -24.18mV   -1.025mV   41.73mV
1.502ns   -14.78mV   -4.282mV   391mV
1.842ns   55.51mV    -9.453mV   1.014V
2.382ns   437.4mV    -11.3mV    1.945V
3.003ns   1.02V      8.115mV    2.429V
3.744ns   1.602V     100.9mV    2.54V
4.805ns   1.977V     371.1mV    2.578V
7.127ns   2.091V     991.8mV    2.59V
9.97ns    2.103V     1.315V     2.59V
[Falling Waveform]
R_fixture= 50.000000
V_fixture= 3.300000
V_fixture_min= 2.700000
V_fixture_max= 3.600000
|time   V(typ)   V(min)   V(max)
0s        3.299V     2.699V     3.599V
1.001ns   3.312V     2.705V     3.6V
1.301ns   3.303V     2.708V     3.38V
1.802ns   3.17V      2.702V     2.386V
2.222ns   2.848V     2.699V     1.449V
2.643ns   2.325V     2.685V     1.087V
3.283ns   1.594V     2.578V     989.7mV
3.944ns   1.323V     2.397V     955mV
6.507ns   1.17V      1.712V     928mV
9.97ns    1.15V      1.521V     925.1mV
[Falling Waveform]
R_fixture= 50.000000
V_fixture= 0.0
V_fixture_min= 0.0
V_fixture_max= 0.0
|time   V(typ)   V(min)   V(max)
0s        2.103V     1.315V     2.59V
360.4ps   2.091V     1.318V     2.571V
580.6ps   2.033V     1.302V     2.384V
800.8ps   1.787V     1.265V     1.707V
1.081ns   1.109V     1.117V     821.1mV
1.421ns   530.9mV    742.7mV    139.1mV
1.602ns   346.8mV    550.5mV    15.64mV
2.062ns   24.35mV    252.4mV    2.164mV
2.923ns   1.652mV    13.82mV    886.3uV
9.97ns    -16.77uV   -27.94uV   -14.14uV
